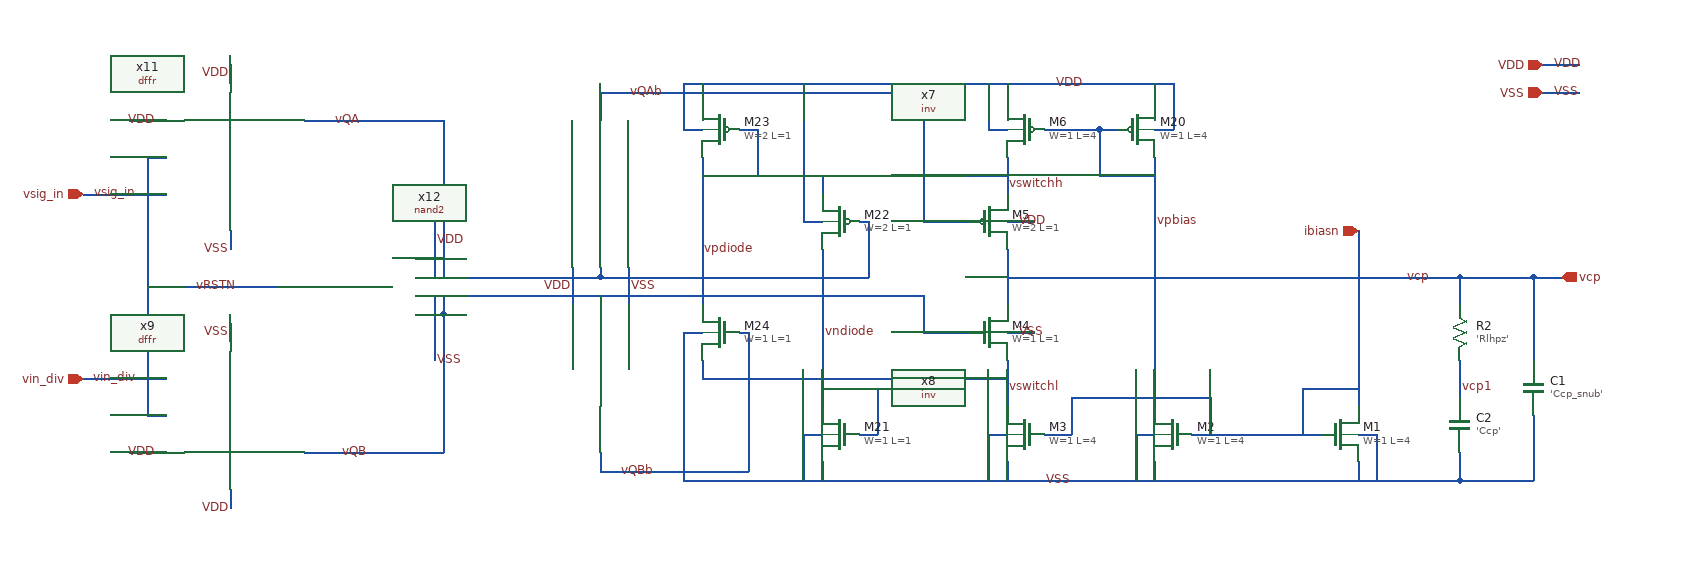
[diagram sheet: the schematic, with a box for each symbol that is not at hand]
v {xschem version=2.9.9 file_version=1.2 }
G {}
K {}
V {}
S {}
E {}
N 60 -280 150 -280 { lab=vin_div}
N 60 -480 150 -480 { lab=vsig_in}
N 1220 -190 1220 -170 { lab=VSS}
N 1200 -220 1220 -220 { lab=VSS}
N 1200 -220 1200 -170 { lab=VSS}
N 1220 -550 1240 -550 { lab=VDD}
N 1220 -600 1220 -580 { lab=VDD}
N 1240 -600 1240 -550 { lab=VDD}
N 1260 -220 1330 -220 { lab=ibiasn}
N 1160 -550 1160 -500 { lab=vpbias}
N 1160 -500 1220 -500 { lab=vpbias}
N 1160 -550 1180 -550 { lab=vpbias}
N 1220 -520 1220 -250 { lab=vpbias}
N 1440 -190 1440 -170 { lab=VSS}
N 1440 -220 1460 -220 { lab=VSS}
N 1460 -220 1460 -170 { lab=VSS}
N 1100 -550 1160 -550 { lab=vpbias}
N 1040 -550 1060 -550 { lab=VDD}
N 1040 -600 1040 -550 { lab=VDD}
N 1060 -600 1060 -580 { lab=VDD}
N 1060 -190 1060 -170 { lab=VSS}
N 1040 -220 1060 -220 { lab=VSS}
N 1040 -220 1040 -170 { lab=VSS}
N 1280 -260 1280 -220 { lab=ibiasn}
N 1130 -260 1280 -260 { lab=ibiasn}
N 1130 -260 1130 -220 { lab=ibiasn}
N 1100 -220 1130 -220 { lab=ibiasn}
N 1060 -520 1060 -480 { lab=vswitchh}
N 1060 -420 1060 -360 { lab=vcp}
N 1060 -300 1060 -250 { lab=vswitchl}
N 1060 -330 1090 -330 { lab=VSS}
N 1060 -450 1090 -450 { lab=VDD}
N 1440 -440 1440 -250 { lab=ibiasn}
N 1380 -270 1440 -270 { lab=ibiasn}
N 1060 -390 1480 -390 { lab=vcp}
N 840 -450 860 -450 { lab=VDD}
N 900 -220 920 -220 { lab=vndiode}
N 920 -270 920 -220 { lab=vndiode}
N 860 -270 920 -270 { lab=vndiode}
N 730 -300 730 -280 { lab=vswitchl}
N 710 -330 730 -330 { lab=VSS}
N 710 -550 730 -550 { lab=VDD}
N 710 -600 710 -550 { lab=VDD}
N 730 -600 730 -580 { lab=VDD}
N 840 -220 860 -220 { lab=VSS}
N 860 -190 860 -170 { lab=VSS}
N 840 -220 840 -170 { lab=VSS}
N 770 -550 790 -550 { lab=vpdiode}
N 790 -550 790 -500 { lab=vpdiode}
N 730 -500 790 -500 { lab=vpdiode}
N 860 -500 1060 -500 { lab=vswitchh}
N 730 -280 1060 -280 { lab=vswitchl}
N 1000 -450 1020 -450 { lab=vQAb}
N 900 -450 910 -450 { lab=vQA}
N 1000 -330 1020 -330 { lab=vQB}
N 770 -330 780 -330 { lab=vQBb}
N 970 -450 1000 -450 { lab=vQAb}
N 970 -370 970 -330 { lab=vQB}
N 970 -330 1000 -330 { lab=vQB}
N 860 -500 860 -480 { lab=vswitchh}
N 860 -420 860 -250 { lab=vndiode}
N 840 -600 840 -450 { lab=VDD}
N 710 -330 710 -170 { lab=VSS}
N 730 -520 730 -360 { lab=vpdiode}
N 300 -560 450 -560 { lab=vQA}
N 300 -200 450 -200 { lab=vQB}
N 130 -380 270 -380 { lab=vRSTN}
N 620 -590 620 -560 { lab=vQAb}
N 620 -200 620 -180 { lab=vQBb}
N 620 -400 620 -390 { lab=vQA}
N 620 -370 620 -360 { lab=vQB}
N 450 -560 450 -390 { lab=vQA}
N 450 -390 620 -390 { lab=vQA}
N 620 -590 970 -590 { lab=vQAb}
N 970 -590 970 -450 { lab=vQAb}
N 620 -390 910 -390 { lab=vQA}
N 910 -450 910 -390 { lab=vQA}
N 450 -370 450 -350 { lab=vQB}
N 450 -370 970 -370 { lab=vQB}
N 620 -180 780 -180 { lab=vQBb}
N 780 -330 780 -180 { lab=vQBb}
N 130 -240 150 -240 { lab=vRSTN}
N 130 -520 130 -240 { lab=vRSTN}
N 130 -520 150 -520 { lab=vRSTN}
N 110 -560 150 -560 { lab=VDD}
N 110 -200 150 -200 { lab=VDD}
N 450 -350 450 -200 { lab=vQB}
N 1330 -220 1400 -220 { lab=ibiasn}
N 1380 -270 1380 -220 { lab=ibiasn}
N 1550 -390 1550 -360 { lab=vcp}
N 1550 -200 1550 -170 { lab=VSS}
N 1550 -300 1550 -260 { lab=vcp1}
N 1480 -390 1550 -390 { lab=vcp}
N 710 -170 1550 -170 { lab=VSS}
N 1550 -390 1630 -390 { lab=vcp}
N 1630 -390 1630 -300 { lab=vcp}
N 1630 -240 1630 -170 { lab=VSS}
N 1550 -170 1630 -170 { lab=VSS}
N 1640 -590 1680 -590 { lab=VSS}
N 1640 -620 1680 -620 { lab=VDD}
N 1630 -390 1660 -390 { lab=vcp}
N 710 -600 1240 -600 { lab=VDD}
N 590 -400 590 -360 { lab=VDD}
N 650 -400 650 -360 { lab=VSS}
N 220 -440 220 -420 { lab=VSS}
N 220 -620 220 -600 { lab=VDD}
N 220 -340 220 -320 { lab=VSS}
N 220 -160 220 -140 { lab=VDD}
N 440 -330 440 -300 { lab=#net1}
N 440 -450 440 -420 { lab=VDD}
N 420 -410 450 -410 {}
N 420 -350 450 -350 {}
N 420 -390 440 -390 {}
N 440 -420 440 -390 {}
N 440 -370 440 -330 {}
N 420 -370 440 -370 {}
C {devices/title.sym} 160 -30 0 0 {name=l1 author="Nikhil Poole"}
C {devices/lab_wire.sym} 120 -480 0 0 {name=l2 sig_type=std_logic lab=vsig_in}
C {devices/lab_wire.sym} 120 -280 0 0 {name=l3 sig_type=std_logic lab=vin_div}
C {devices/lab_wire.sym} 1220 -450 0 1 {name=l6 sig_type=std_logic lab=vpbias}
C {sky130_fd_pr/nfet_01v8.sym} 1420 -220 0 0 {name=M1
L=4
W=1
nf=1 
mult=10
ad="'int((nf+1)/2) * W/nf * 0.29'" 
pd="'2*int((nf+1)/2) * (W/nf + 0.29)'"
as="'int((nf+2)/2) * W/nf * 0.29'" 
ps="'2*int((nf+2)/2) * (W/nf + 0.29)'"
nrd="'0.29 / W'" nrs="'0.29 / W'"
sa=0 sb=0 sd=0
model=nfet_01v8
spiceprefix=X
}
C {sky130_fd_pr/nfet_01v8.sym} 1240 -220 0 1 {name=M2
L=4
W=1
nf=1 
mult=1
ad="'int((nf+1)/2) * W/nf * 0.29'" 
pd="'2*int((nf+1)/2) * (W/nf + 0.29)'"
as="'int((nf+2)/2) * W/nf * 0.29'" 
ps="'2*int((nf+2)/2) * (W/nf + 0.29)'"
nrd="'0.29 / W'" nrs="'0.29 / W'"
sa=0 sb=0 sd=0
model=nfet_01v8
spiceprefix=X
}
C {sky130_fd_pr/nfet_01v8.sym} 1080 -220 0 1 {name=M3
L=4
W=1
nf=1 
mult=1
ad="'int((nf+1)/2) * W/nf * 0.29'" 
pd="'2*int((nf+1)/2) * (W/nf + 0.29)'"
as="'int((nf+2)/2) * W/nf * 0.29'" 
ps="'2*int((nf+2)/2) * (W/nf + 0.29)'"
nrd="'0.29 / W'" nrs="'0.29 / W'"
sa=0 sb=0 sd=0
model=nfet_01v8
spiceprefix=X
}
C {sky130_fd_pr/nfet_01v8_lvt.sym} 1040 -330 0 0 {name=M4
L=1
W=1
nf=1
mult=1
ad="'int((nf+1)/2) * W/nf * 0.29'" 
pd="'2*int((nf+1)/2) * (W/nf + 0.29)'"
as="'int((nf+2)/2) * W/nf * 0.29'" 
ps="'2*int((nf+2)/2) * (W/nf + 0.29)'"
nrd="'0.29 / W'" nrs="'0.29 / W'"
sa=0 sb=0 sd=0
model=nfet_01v8_lvt
spiceprefix=X
}
C {sky130_fd_pr/pfet_01v8_lvt.sym} 1040 -450 0 0 {name=M5
L=1
W=2
nf=1
mult=1
ad="'int((nf+1)/2) * W/nf * 0.29'" 
pd="'2*int((nf+1)/2) * (W/nf + 0.29)'"
as="'int((nf+2)/2) * W/nf * 0.29'" 
ps="'2*int((nf+2)/2) * (W/nf + 0.29)'"
nrd="'0.29 / W'" nrs="'0.29 / W'"
sa=0 sb=0 sd=0
model=pfet_01v8_lvt
spiceprefix=X
}
C {sky130_fd_pr/pfet_01v8.sym} 1080 -550 0 1 {name=M6
L=4
W=1
nf=1
mult=8
ad="'int((nf+1)/2) * W/nf * 0.29'" 
pd="'2*int((nf+1)/2) * (W/nf + 0.29)'"
as="'int((nf+2)/2) * W/nf * 0.29'" 
ps="'2*int((nf+2)/2) * (W/nf + 0.29)'"
nrd="'0.29 / W'" nrs="'0.29 / W'"
sa=0 sb=0 sd=0
model=pfet_01v8
spiceprefix=X
}
C {sky130_fd_pr/pfet_01v8.sym} 1200 -550 0 0 {name=M20
L=4
W=1
nf=1
mult=8
ad="'int((nf+1)/2) * W/nf * 0.29'" 
pd="'2*int((nf+1)/2) * (W/nf + 0.29)'"
as="'int((nf+2)/2) * W/nf * 0.29'" 
ps="'2*int((nf+2)/2) * (W/nf + 0.29)'"
nrd="'0.29 / W'" nrs="'0.29 / W'"
sa=0 sb=0 sd=0
model=pfet_01v8
spiceprefix=X
}
C {devices/capa.sym} 1550 -230 0 0 {name=C2
m=1
value='Ccp'
footprint=1206
device="ceramic capacitor"}
C {devices/lab_wire.sym} 370 -200 0 0 {name=l37 sig_type=std_logic lab=vQB}
C {devices/lab_wire.sym} 1060 -490 0 1 {name=l38 sig_type=std_logic lab=vswitchh}
C {devices/lab_wire.sym} 1060 -270 0 1 {name=l39 sig_type=std_logic lab=vswitchl}
C {sky130_fd_pr/nfet_01v8.sym} 880 -220 0 1 {name=M21
L=1
W=1
nf=1 
mult=1
ad="'int((nf+1)/2) * W/nf * 0.29'" 
pd="'2*int((nf+1)/2) * (W/nf + 0.29)'"
as="'int((nf+2)/2) * W/nf * 0.29'" 
ps="'2*int((nf+2)/2) * (W/nf + 0.29)'"
nrd="'0.29 / W'" nrs="'0.29 / W'"
sa=0 sb=0 sd=0
model=nfet_01v8
spiceprefix=X
}
C {sky130_fd_pr/pfet_01v8.sym} 880 -450 0 1 {name=M22
L=1
W=2
nf=1
mult=1
ad="'int((nf+1)/2) * W/nf * 0.29'" 
pd="'2*int((nf+1)/2) * (W/nf + 0.29)'"
as="'int((nf+2)/2) * W/nf * 0.29'" 
ps="'2*int((nf+2)/2) * (W/nf + 0.29)'"
nrd="'0.29 / W'" nrs="'0.29 / W'"
sa=0 sb=0 sd=0
model=pfet_01v8
spiceprefix=X
}
C {devices/lab_wire.sym} 330 -560 0 1 {name=l40 sig_type=std_logic lab=vQA}
C {sky130_fd_pr/pfet_01v8.sym} 750 -550 0 1 {name=M23
L=1
W=2
nf=1
mult=1
ad="'int((nf+1)/2) * W/nf * 0.29'" 
pd="'2*int((nf+1)/2) * (W/nf + 0.29)'"
as="'int((nf+2)/2) * W/nf * 0.29'" 
ps="'2*int((nf+2)/2) * (W/nf + 0.29)'"
nrd="'0.29 / W'" nrs="'0.29 / W'"
sa=0 sb=0 sd=0
model=pfet_01v8
spiceprefix=X
}
C {sky130_fd_pr/nfet_01v8.sym} 750 -330 0 1 {name=M24
L=1
W=1
nf=1 
mult=1
ad="'int((nf+1)/2) * W/nf * 0.29'" 
pd="'2*int((nf+1)/2) * (W/nf + 0.29)'"
as="'int((nf+2)/2) * W/nf * 0.29'" 
ps="'2*int((nf+2)/2) * (W/nf + 0.29)'"
nrd="'0.29 / W'" nrs="'0.29 / W'"
sa=0 sb=0 sd=0
model=nfet_01v8
spiceprefix=X
}
C {devices/lab_wire.sym} 680 -180 0 0 {name=l41 sig_type=std_logic lab=vQBb}
C {devices/lab_wire.sym} 1490 -390 0 1 {name=l44 sig_type=std_logic lab=vcp}
C {devices/lab_wire.sym} 180 -380 0 1 {name=l49 sig_type=std_logic lab=vRSTN}
C {/home/users/nhpoole/ee272b/ee272b_mixed_signal_mmwave_accelerator/designs/inv.sym} 620 -450 3 0 {name=x7 M=1}
C {/home/users/nhpoole/ee272b/ee272b_mixed_signal_mmwave_accelerator/designs/inv.sym} 620 -310 3 1 {name=x8 M=1}
C {devices/lab_wire.sym} 690 -590 0 0 {name=l50 sig_type=std_logic lab=vQAb}
C {/home/users/nhpoole/ee272b/ee272b_mixed_signal_mmwave_accelerator/designs/dffr.sym} 220 -240 2 1 {name=x9 M=1}
C {/home/users/nhpoole/ee272b/ee272b_mixed_signal_mmwave_accelerator/designs/dffr.sym} 220 -520 0 0 {name=x11 M=1}
C {/home/users/nhpoole/ee272b/ee272b_mixed_signal_mmwave_accelerator/designs/nand2.sym} 350 -380 0 1 {name=x12 M=1}
C {devices/res.sym} 1550 -330 0 0 {name=R2
value='Rlhpz'
footprint=1206
device=resistor
m=1}
C {devices/noconn.sym} 300 -280 0 1 {name=l11}
C {devices/noconn.sym} 300 -480 0 1 {name=l13}
C {devices/lab_wire.sym} 1550 -270 0 1 {name=l4 sig_type=std_logic lab=vcp1}
C {devices/capa.sym} 1630 -270 0 0 {name=C1
m=1
value='Ccp_snub'
footprint=1206
device="ceramic capacitor"}
C {devices/lab_wire.sym} 1110 -600 0 1 {name=l8 sig_type=std_logic lab=VDD}
C {devices/lab_wire.sym} 1100 -170 0 1 {name=l9 sig_type=std_logic lab=VSS}
C {devices/lab_wire.sym} 1070 -330 0 1 {name=l7 sig_type=std_logic lab=VSS}
C {devices/lab_wire.sym} 1070 -450 0 1 {name=l10 sig_type=std_logic lab=VDD}
C {devices/lab_wire.sym} 140 -560 0 0 {name=l12 sig_type=std_logic lab=VDD}
C {devices/lab_wire.sym} 140 -200 0 0 {name=l14 sig_type=std_logic lab=VDD}
C {devices/ipin.sym} 1640 -620 0 0 {name=p1 lab=VDD}
C {devices/ipin.sym} 1640 -590 0 0 {name=p2 lab=VSS}
C {devices/lab_wire.sym} 1650 -590 0 1 {name=l20 sig_type=std_logic lab=VSS}
C {devices/lab_wire.sym} 1650 -620 0 1 {name=l21 sig_type=std_logic lab=VDD}
C {devices/ipin.sym} 60 -280 0 0 {name=p3 lab=vin_div}
C {devices/ipin.sym} 60 -480 0 0 {name=p4 lab=vsig_in}
C {devices/opin.sym} 1660 -390 0 0 {name=p5 lab=vcp}
C {devices/ipin.sym} 1440 -440 1 0 {name=p6 lab=ibiasn}
C {devices/lab_wire.sym} 650 -380 0 1 {name=l5 sig_type=std_logic lab=VSS}
C {devices/lab_wire.sym} 590 -380 0 0 {name=l15 sig_type=std_logic lab=VDD}
C {devices/lab_wire.sym} 860 -330 0 1 {name=l16 sig_type=std_logic lab=vndiode}
C {devices/lab_wire.sym} 730 -420 0 1 {name=l17 sig_type=std_logic lab=vpdiode}
C {devices/lab_wire.sym} 220 -610 0 0 {name=l18 sig_type=std_logic lab=VDD}
C {devices/lab_wire.sym} 220 -420 0 0 {name=l19 sig_type=std_logic lab=VSS}
C {devices/lab_wire.sym} 220 -330 0 0 {name=l22 sig_type=std_logic lab=VSS}
C {devices/lab_wire.sym} 220 -140 0 0 {name=l23 sig_type=std_logic lab=VDD}
C {devices/lab_wire.sym} 440 -430 0 1 {name=l24 sig_type=std_logic lab=VDD}
C {devices/lab_wire.sym} 440 -300 0 1 {name=l25 sig_type=std_logic lab=VSS}
